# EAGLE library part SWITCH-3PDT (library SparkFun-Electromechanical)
Three-pole, double-throw stomp switch. Drawn as three separate gates for schematic clarity.

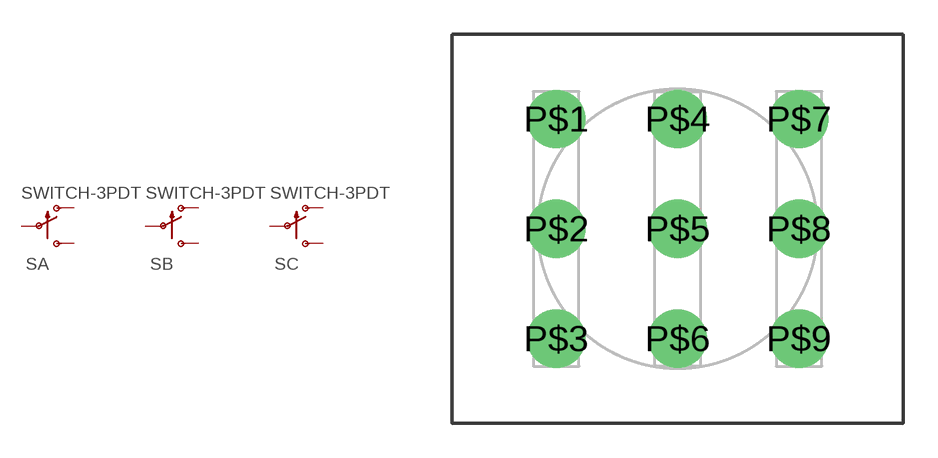
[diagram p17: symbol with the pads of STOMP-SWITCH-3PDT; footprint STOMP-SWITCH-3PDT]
Designator prefix S; gates A=SW_SPDT_POL B=SW_SPDT_POL C=SW_SPDT_POL

## SWITCH-3PDT (PROD_ID: SWCH-13197)  [STOMP-SWITCH-3PDT]
P$1  A:O  pas
P$2  A:P  pas
P$3  A:S  pas
P$4  B:O  pas
P$5  B:P  pas
P$6  B:S  pas
P$7  C:O  pas
P$8  C:P  pas
P$9  C:S  pas

## Footprint STOMP-SWITCH-3PDT (pad centres in mm)
drill 1.2 pad 2.54: P$1 -5.3,4.8; P$2 -5.3,0; P$3 -5.3,-4.8; P$4 0,4.8; P$5 0,0; P$6 0,-4.8; P$7 5.3,4.8; P$8 5.3,0; P$9 5.3,-4.8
